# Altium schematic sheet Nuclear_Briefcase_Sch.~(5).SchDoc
size A; SheetNumber: 1; SheetTotal: 1

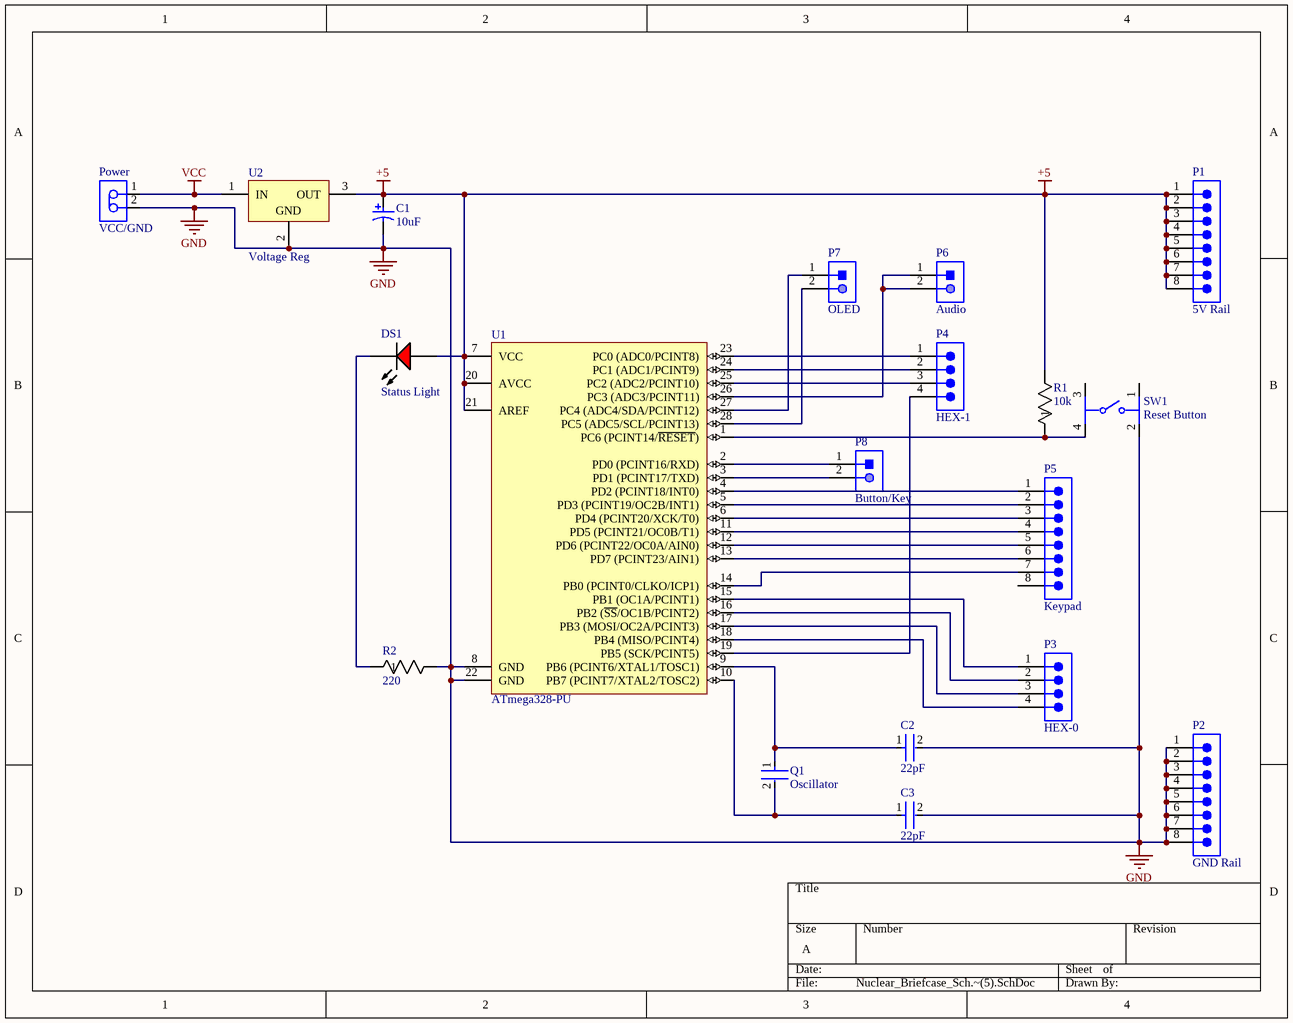
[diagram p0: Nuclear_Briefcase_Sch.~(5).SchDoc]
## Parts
C1  10uF  [CAPPR55-200-1100X500X1200]
C2  22pF  [FP-RCE0DB-MFG]
C3  22pF  [FP-RCE0DB-MFG]
DS1  Status Light  [LED-2P-2.28-3MM_A]
P1  5V Rail  [691321300008]
P2  GND Rail  [691321300008]
P3  HEX-0  [61300411121]
P4  HEX-1  [61300411121]
P5  Keypad  [691321300008]
P6  Audio  [JST-S2B-XH-A(LF)(SN)_V]
P7  OLED  [JST-S2B-XH-A(LF)(SN)_V]
P8  Button/Key  [JST-S2B-XH-A(LF)(SN)_V]
Power  VCC/GND  [TECO-640456-2_V]
Q1  Oscillator  [FP-RCE0DB-MFG]
R1  10k  [RES_AC07_VIS]
R2  220  [RES_AC05_VIS]
SW1  Reset Button  [FP-PTS645SM43SMTR92LFS-MFG]
U1  ATmega328-PU  [28P3]
U2  Voltage Reg  [TO220]

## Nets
+5: C1.1 DS1.1(A) P1.1 P1.2 P1.3 P1.4 P1.5 P1.6 P1.7 P1.8 R1.2 U1.7(VCC) U1.20(AVCC) U1.21(AREF) U2.3(OUT)
GND: C1.2 C2.2 C3.2 P2.1 P2.2 P2.3 P2.4 P2.5 P2.6 P2.7 P2.8 Power.2 R2.2 SW1.2 U1.8(GND) U1.22(GND) U2.2(GND)
VCC: Power.1 U2.1(IN)
NetC2_1: C2.1 Q1.1 U1.9(PB6_(PCINT6/XTAL1/TOSC1))
NetC3_1: C3.1 Q1.2 U1.10(PB7_(PCINT7/XTAL2/TOSC2))
NetDS1_2: DS1.2(K) R2.1
NetP3_1: P3.1 U1.15(PB1_(OC1A/PCINT1))
NetP3_2: P3.2 U1.16(PB2_(~{SS}/OC1B/PCINT2))
NetP3_3: P3.3 U1.17(PB3_(MOSI/OC2A/PCINT3))
NetP3_4: P3.4 U1.18(PB4_(MISO/PCINT4))
NetP4_1: P4.1 U1.23(PC0_(ADC0/PCINT8))
NetP4_2: P4.2 U1.24(PC1_(ADC1/PCINT9))
NetP4_3: P4.3 U1.25(PC2_(ADC2/PCINT10))
NetP4_4: P4.4 U1.19(PB5_(SCK/PCINT5))
NetP5_1: P5.1 U1.4(PD2_(PCINT18/INT0))
NetP5_2: P5.2 U1.5(PD3_(PCINT19/OC2B/INT1))
NetP5_3: P5.3 U1.6(PD4_(PCINT20/XCK/T0))
NetP5_4: P5.4 U1.11(PD5_(PCINT21/OC0B/T1))
NetP5_5: P5.5 U1.12(PD6_(PCINT22/OC0A/AIN0))
NetP5_6: P5.6 U1.13(PD7_(PCINT23/AIN1))
NetP5_7: P5.7 U1.14(PB0_(PCINT0/CLKO/ICP1))
NetP6_1: P6.1 P6.2 U1.26(PC3_(ADC3/PCINT11))
NetP7_1: P7.1 U1.27(PC4_(ADC4/SDA/PCINT12))
NetP7_2: P7.2 U1.28(PC5_(ADC5/SCL/PCINT13))
NetP8_1: P8.1 U1.2(PD0_(PCINT16/RXD))
NetP8_2: P8.2 U1.3(PD1_(PCINT17/TXD))
NetR1_1: R1.1 SW1.4 U1.1(PC6_(PCINT14/~{RESET}))

Not connected (* = marked no-connect by the designer): P5 8; SW1 1 3

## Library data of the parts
C1 = CMP-1665-00038-2: Aluminum Electrolytic Capacitor, 10 uF, +/- 20%, 50 V, -40 to 85 degC, 2-Pin THD, RoHS, Bulk; Manufacturer: Panasonic; Life (Hours): 2000Hour; Lead/Base Style: Straight; Dissipation Factor: 0.12%; Leakage Current: 3uA; Dielectric Material: Aluminium; Lead Diameter: 0.5mm; Voltage Rating: 50V; Ripple Current: 65mA
C2 C3 Q1 = CMP-06035-047347-1: Cap Ceramic 22pF 100V C0G ±5% Radial 2.5mm +125°C Ammo Pack; Lead Diameter: 0.5mm; Lead/Base Style: Straight
DS1 = CMP-007-00007-2: Red LED, 80 mW, 30 mA, -25 to 85 degC, 2-Pin THD; Manufacturer: Shenzhen CGX
P1 P2 P5 = CMP-002-00073-1: Barrier Strip Terminal Block, 10A, 1 Row(s), 1 Deck(s); Manufacturer Series: 321
P3 P4 = CMP-002-00093-1: Board Connector, 4 Contact(s), 1 Row(s), Male, Straight, 0.1 inch Pitch, Solder Terminal, Locking, Black Insulator, Plug; Body Length: 0.4inch; Rated Current (Signal): 3A; Number of Rows Loaded: 1; Reliability: COMMERCIAL; Contact Style: SQ PIN-SKT; Contact Resistance: 20mR; Dielectric Withstanding Voltage (AC): 500V; Contact Pattern: RECTANGULAR; Reference Standard: UL; Insulation Resistance: 1GR; Number of Contacts: 4
P6-P8 = CMP-002-00032-2: Male Header, Pitch 2.5 mm, 1 x 2 Position, Height 6.1 mm, Tail Length 3.4 mm, -25 to 85 degC, RoHS, Bulk; Manufacturer: JST
Power = CMP-2000-05417-1: Male Header, Pitch 2.54 mm, 1 x 2 Position, Height 10.49 mm, Tail Length 3.556 mm, -55 to 105 degC, RoHS, Bulk; Manufacturer: TE Connectivity; Standards: RoHSCompliant,ELVCompliant,UL94V-0; Material, Housing: Polyester; Agency Approvals: CSA,UL; Brand/Series: MTA-100Series; Contact Centerline Spacing: 0.100 / in.; Material, Contact: CopperAlloy; Current, Rating: 5 / A; Color, Housing: White; Contact Termination Area Plating: Tin; Special Features: Pinstrip; Number of Positions: 2; Pin Spacing: 0.1 / "; Temperature, Operating: -55to+105 / degC; Angle: Straight; Mount Angle: Vertical; Connector Type: MTA-100; Primary Type: InterconnectSystem; Voltage, Rating: 250 / V; Mounting Hole Size: 0.04 / "
R1 = CMP-00030-42824152-1: AC07000001002JAC00 Resistor, 10 kOhm, ± 5%, 7 W, Axial Leaded, Wirewound, General Purpose; Voltage Rating (DC): 265V; Power Rating: 7W; Temperature Coefficient: 180ppm/°C; Resistance: 10kΩ
R2 = CMP-00030-39746845-1: AC05000002200JAC00 Resistor, 220 Ohm, ± 5%, 5 W, Axial Leaded, Wirewound, General Purpose; Lead Diameter: 800µm; Resistance: 220Ω; Voltage Rating: 33V; Temperature Coefficient: -10ppm/°C; Power Rating: 5W
SW1 = CMP-2000-05160-2: SWITCH TACTILE SPST-NO 0.05A 12V; Contact Resistance: 100mR; Throw Configuration: SPST; Illumination Type: Non-Illuminated; Mechanical Life: 100000Cycles; Current Rating: 50mA; Switch Function: Off-Mom; Actuator Length: 0.85mm; Actuator Material: Nylon; Actuator Type: Standard; Operating Force: 160gf
U1 = CMP-0095-00015-2: 8-bit AVR Microcontroller, 32KB Flash, 1KB EEPROM, 2KB SRAM, 28-pin PDIP, Industrial Grade (-40°C to 85°C)
U2 = CMP-019-00018-3: Positive Voltage Regulator IC, 1.5 A, 5 V, 0 to 125 degC, 3-Pin TO-220, RoHS, Tube; Manufacturer: STMicroelectronics; Max Input Voltage: 35V; Min Supply Voltage: 8V; Nominal Output Voltage: 5V; Outputs: 1; Output Current: 1.5A; Dropout Voltage: 2V; Max Supply Voltage: 20V; Min Input Voltage: 7V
